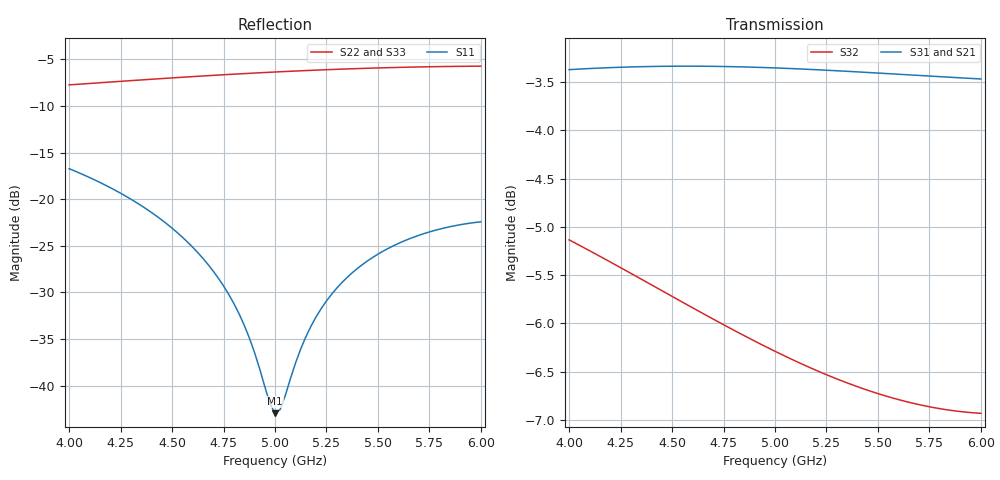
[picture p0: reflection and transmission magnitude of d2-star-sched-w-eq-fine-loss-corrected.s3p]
! yapnr Order 0 prediction d2-star-sched-w-eq-fine: predictions/D2/runs/d2-star-sched/fine.s3p, loss-corrected
! substrate W-eq; coupon model OSHPARK-4L-FR408HR; correction: ratio (port line)
! |S21|, |S31| (and S12, S13) scaled, phases kept; 50 ohm, e^(+jwt)
# GHz S RI R 50
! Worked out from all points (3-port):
!   81 points, 4 GHz to 6 GHz, reference 50 ohm
!   strongest paths, dB at 4 GHz, 4.5 GHz, 5 GHz, 5.5 GHz, 6 GHz:
!     S31: -3.4, -3.3, -3.4, -3.4, -3.5
!     S21: -3.4, -3.3, -3.4, -3.4, -3.5
!     S32: -5.1, -5.7, -6.3, -6.7, -6.9
!   lowest |S11| = -43.0 dB at 5 GHz (marker M1), VSWR 1.01, Z = 49.7 + j0.634 ohm
!   |S11| at or under -10 dB: start of sweep to end of sweep
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4  0.0373 0.141  -0.6591 -0.1607  -0.6591 -0.1607
   -0.6589 -0.1613  0.3538 -0.2085  -0.4546 0.3161
   -0.6589 -0.1613  -0.4546 0.3161  0.3538 -0.2085
4.375  0.0417 0.0783  -0.6793 0.039  -0.6793 0.039
       -0.6798 0.0379  0.2753 -0.3411  -0.3102 0.4255
       -0.6798 0.0379  -0.3102 0.4255  0.2753 -0.3411
4.65  0.0279 0.0393  -0.6545 0.1857  -0.6545 0.1857
      -0.6556 0.1846  0.1911 -0.4166  -0.1951 0.468
      -0.6556 0.1846  -0.1951 0.468  0.1911 -0.4166
4.825  0.0136 0.0202  -0.6214 0.2748  -0.6214 0.2748
       -0.6231 0.2739  0.1287 -0.4524  -0.1225 0.4801
       -0.6231 0.2739  -0.1225 0.4801  0.1287 -0.4524
5  -0.00314 0.00638  -0.5759 0.3582  -0.5759 0.3582
   -0.5781 0.3576  0.0615 -0.4775  -0.0523 0.4819
   -0.5781 0.3576  -0.0523 0.4819  0.0615 -0.4775
5.025  -0.00565 0.00486  -0.5685 0.3696  -0.5685 0.3696
       -0.5707 0.369  0.0516 -0.4802  -0.0425 0.4814
       -0.5707 0.369  -0.0425 0.4814  0.0516 -0.4802
5.175  -0.0208 -0.00189  -0.5191 0.4341  -0.5191 0.4341
       -0.5216 0.434  -0.0086 -0.4913  0.0145 0.4749
       -0.5216 0.434  0.0145 0.4749  -0.0086 -0.4913
5.35  -0.0377 -0.00484  -0.4522 0.5009  -0.4522 0.5009
      -0.4548 0.5015  -0.0796 -0.4936  0.0771 0.4604
      -0.4548 0.5015  0.0771 0.4604  -0.0796 -0.4936
5.625  -0.0596 -0.000506  -0.3304 0.5848  -0.3304 0.5848
       -0.333 0.5865  -0.1886 -0.4743  0.1667 0.4253
       -0.333 0.5865  0.1667 0.4253  -0.1886 -0.4743
6  -0.0741 0.0155  -0.1416 0.6524  -0.1416 0.6524
   -0.1431 0.6554  -0.3204 -0.4063  0.2722 0.3585
   -0.1431 0.6554  0.2722 0.3585  -0.3204 -0.4063
